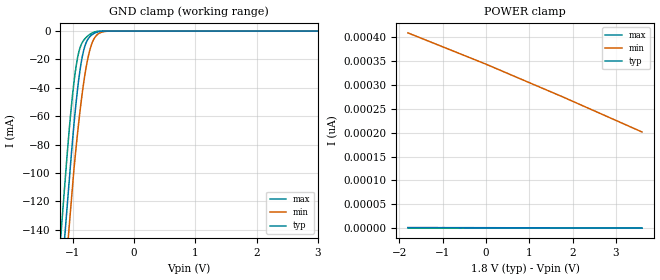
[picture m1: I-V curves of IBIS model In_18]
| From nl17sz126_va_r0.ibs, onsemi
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|//////////////////////////////////////////////////////////////////////////////
|//////////////////////////////////////////////////////////////////////////////
[Model]  In_18
Model_type Input
Vinh =  1.17
Vinl =  0.63
|  variable   typ   min   max
C_comp   2.6pF   2.6pF   2.6pF
|//////////////////////////////////////////////////////////////////////////////
[Temperature Range]   25   125   -55
|//////////////////////////////////////////////////////////////////////////////
[Voltage Range]   1.80V   1.65V   1.95V
|//////////////////////////////////////////////////////////////////////////////
[POWER Clamp Reference] 1.80V   1.65V   1.95V
|//////////////////////////////////////////////////////////////////////////////
[GND Clamp Reference]   0V   0V   0V
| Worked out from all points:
|   GND clamp passes 1 mA (typ) near -0.62 V on its own axis
|//////////////////////////////////////////////////////////////////////////////
[GND Clamp]
|   Voltage   I(typ)   I(min)   I(max)
-2V       -613.5mA   -628.6mA   -592.9mA
-1.22V    -193.3mA   -222.4mA   -158.8mA
-1.18V    -171.8mA   -201.5mA   -136.5mA
-1.12V    -139.5mA   -170.3mA   -103.1mA
-1.06V    -107.1mA   -139mA     -71.09mA
-960mV    -56.79mA   -88.47mA   -29.4mA
-880mV    -27.22mA   -56.09mA   -11.66mA
-800mV    -10.34mA   -30.41mA   -5.326mA
-700mV    -3.054mA   -10.3mA    -1.722mA
-600mV    -709.9uA   -2.508mA   -209.3uA
-420mV    -3.627uA   -71.28uA   -127.6nA
4V        1.285pA    434.4pA    184.2fA
|//////////////////////////////////////////////////////////////////////////////
[POWER Clamp]
|   Voltage   I(typ)   I(min)   I(max)
-1.8V     1.206pA    408.9pA    166.2fA
0V        850.5fA    343.4pA    85.17fA
1.8V      494.8fA    273.7pA    4.109fA
3.6V      139.1fA    201.4pA    -76.95fA
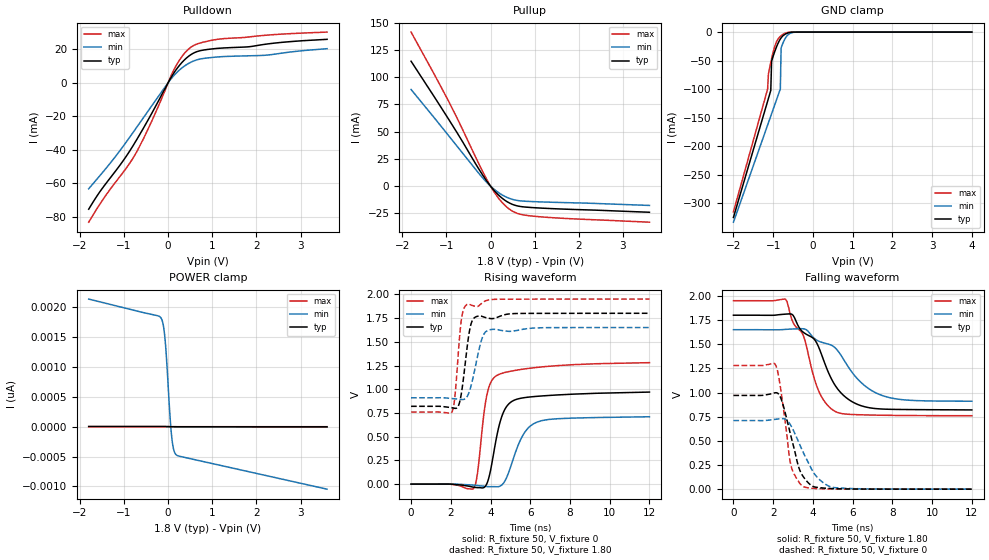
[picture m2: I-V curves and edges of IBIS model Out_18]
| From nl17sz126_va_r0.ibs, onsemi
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|//////////////////////////////////////////////////////////////////////////////
|//////////////////////////////////////////////////////////////////////////////
[Model] Out_18
Model_type 3-state
Polarity Non-Inverting
Enable Active-High
Vmeas = 0.90
Vref = 1.8
Rref = 500
Cref = 50pF
|  variable   typ   min   max
C_comp   3.9pF   3.9pF   3.9pF
|//////////////////////////////////////////////////////////////////////////////
[Temperature Range]   25   125   -55
|//////////////////////////////////////////////////////////////////////////////
[Voltage Range]   1.80V   1.65V   1.95V
|//////////////////////////////////////////////////////////////////////////////
[Pulldown Reference]   0V   0V   0V
|//////////////////////////////////////////////////////////////////////////////
[Pullup Reference]   1.80V   1.65V   1.95V
|//////////////////////////////////////////////////////////////////////////////
[GND Clamp Reference]   0V   0V   0V
|//////////////////////////////////////////////////////////////////////////////
[POWER Clamp Reference] 1.80V   1.65V   1.95V
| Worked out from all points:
|   slope of the pulldown table from 0 to 0.27 V, typ, clamps not added: 25 ohm
|   slope of the pullup table from 0 to 0.27 V, typ, clamps not added: 23.9 ohm
|   GND clamp passes 1 mA (typ) near -0.60 V on its own axis
|   falling waveform, R_fixture 50, V_fixture 1.80: 20-80 % time 1.67ns typ, 1.93ns min, 1.29ns max; typ from 1.8 V to 0.82 V
|   falling waveform, R_fixture 50, V_fixture 0: 20-80 % time 722ps typ, 1.03ns min, 498ps max; typ from 0.97 V to 0 V
|   rising waveform, R_fixture 50, V_fixture 0: 20-80 % time 646ps typ, 855ps min, 499ps max; typ from 0 V to 0.97 V
|   rising waveform, R_fixture 50, V_fixture 1.80: 20-80 % time 356ps typ, 478ps min, 279ps max; typ from 0.82 V to 1.8 V
|//////////////////////////////////////////////////////////////////////////////
[Pulldown]
|   Voltage   I(typ)   I(min)   I(max)
-1.8V     -75.54mA   -63.35mA   -83.29mA
-1.45V    -61.61mA   -52.47mA   -68.7mA
-1.05V    -47.73mA   -39.08mA   -54.57mA
-790mV    -37.4mA    -29.54mA   -44.8mA
-460mV    -22.5mA    -17.14mA   -27.98mA
150mV     6.578mA    4.834mA    8.675mA
330mV     12.56mA    9.171mA    16.24mA
480mV     16.09mA    11.74mA    20.46mA
690mV     18.84mA    13.9mA     23.39mA
1.12V     20.48mA    15.35mA    25.9mA
2.22V     23.01mA    16.41mA    28.34mA
3.6V      25.88mA    20.3mA     30.2mA
|//////////////////////////////////////////////////////////////////////////////
[Pullup]
|   Voltage   I(typ)   I(min)   I(max)
-1.8V     114.6mA    88.69mA    141.4mA
-960mV    62.08mA    46.84mA    78.73mA
-760mV    49.17mA    36.73mA    62.68mA
-280mV    16.69mA    12.48mA    21.77mA
-40mV     2.125mA    1.556mA    2.846mA
160mV     -7.332mA   -5.342mA   -9.914mA
280mV     -11.61mA   -8.452mA   -15.76mA
400mV     -14.86mA   -10.8mA    -20.26mA
520mV     -17.1mA    -12.41mA   -23.45mA
640mV     -18.42mA   -13.34mA   -25.42mA
1V        -19.82mA   -14.25mA   -27.68mA
3.6V      -23.98mA   -17.71mA   -33.08mA
|//////////////////////////////////////////////////////////////////////////////
[GND Clamp]
|   Voltage   I(typ)   I(min)   I(max)
-2V       -324.9mA   -333.3mA   -315mA
-1.14V    -121.2mA   -163mA     -99.88mA
-1.12V    -116.5mA   -159mA     -73.89mA
-1.06V    -102.2mA   -147.2mA   -52.96mA
-1.04V    -51.21mA   -143.2mA   -46.66mA
-960mV    -34.1mA    -127.4mA   -25.27mA
-820mV    -12.17mA   -99.64mA   -7.555mA
-800mV    -10.11mA   -27.8mA    -6.375mA
-700mV    -3.742mA   -11.47mA   -2.068mA
-620mV    -1.325mA   -4.378mA   -418uA
-380mV    -1.233uA   -37.51uA   -18.43nA
4V        323.3fA    -65.59pA   221.9fA
|//////////////////////////////////////////////////////////////////////////////
[POWER Clamp]
|   Voltage   I(typ)   I(min)   I(max)
-1.8V     4.117pA    2.139nA    202.9fA
-240mV    3.159pA    1.86nA     84.37fA
-160mV    3.11pA     1.82nA     78.3fA
-110mV    3.061pA    1.701nA    74.5fA
-70mV     2.893pA    1.462nA    71.46fA
-30mV     2.356pA    1.06nA     68.42fA
40mV      562.2fA    194.7pA    63.1fA
80mV      -372.3fA   -168.2pA   60.06fA
100mV     -714fA     -286.9pA   58.54fA
130mV     -1.056pA   -397.4pA   56.26fA
190mV     -1.301pA   -476.2pA   51.7fA
3.6V      -3.649pA   -1.047nA   -207.4fA
|//////////////////////////////////////////////////////////////////////////////
|//////////////////////////////////////////////////////////////////////////////
[Ramp]
|  variable   typ   min   max
R_load = 50
dV/dt_r   5.820E-01/6.500E-10  4.260E-01/8.500E-10  7.680E-01/5.000E-10
dV/dt_f   5.880E-01/1.725E-09  4.440E-01/1.950E-09  7.140E-01/1.275E-09
|//////////////////////////////////////////////////////////////////////////////
[Falling Waveform]
R_fixture = 50
V_fixture = 1.80
V_fixture_min = 1.65
V_fixture_max = 1.95
C_fixture = 0p
|   time   V(typ)   V(min)   V(max)
0s        1.8V       1.65V      1.95V
2.625ns   1.811V     1.653V     1.965V
3ns       1.8V       1.658V     1.725V
3.525ns   1.622V     1.66V      1.587V
4.275ns   1.477V     1.533V     1.024V
4.65ns    1.274V     1.508V     889.4mV
5.175ns   1.057V     1.451V     799.2mV
6.3ns     873mV      1.129V     770.3mV
7.425ns   829.8mV    973.9mV    765.2mV
12ns      820mV      910mV      760mV
|//////////////////////////////////////////////////////////////////////////////
[Falling Waveform]
R_fixture = 50
V_fixture = 0
C_fixture = 0p
|   time   V(typ)   V(min)   V(max)
0s        970mV      710mV      1.28V
2.1ns     997.4mV    722.4mV    1.293V
2.2ns     995.9mV    725.1mV    1.24V
2.35ns    958.5mV    729.1mV    1.074V
2.9ns     543.5mV    655.6mV    240.6mV
3.25ns    251.5mV    502mV      87.28mV
3.5ns     133.8mV    385.9mV    28.27mV
4.15ns    20mV       138.8mV    6.418mV
4.95ns    6.178mV    21.12mV    1.968mV
12ns      0V         0V         0V
|//////////////////////////////////////////////////////////////////////////////
[Rising Waveform]
R_fixture = 50
V_fixture = 0
C_fixture = 0p
|   time   V(typ)   V(min)   V(max)
0s        0V         0V         0V
3.15ns    -32.59mV   -10.29mV   -44.69mV
3.35ns    -36.72mV   -15.08mV   124.1mV
3.8ns     -1.854mV   -24.88mV   922.8mV
4ns       144.1mV    -26.92mV   1.067V
4.35ns    542.1mV    -27.5mV    1.149V
4.95ns    851.7mV    144.8mV    1.187V
5.6ns     907.9mV    504.2mV    1.21V
6.35ns    925.5mV    654.5mV    1.23V
12ns      970mV      710mV      1.28V
|//////////////////////////////////////////////////////////////////////////////
[Rising Waveform]
R_fixture = 50
V_fixture = 1.80
V_fixture_min = 1.65
V_fixture_max = 1.95
C_fixture = 0p
|   time   V(typ)   V(min)   V(max)
0s        820mV      910mV      760mV
2.05ns    805.2mV    902.1mV    757.7mV
2.2ns     799.3mV    899.2mV    912.4mV
2.525ns   946.3mV    891.9mV    1.723V
2.825ns   1.447V     923.5mV    1.894V
2.975ns   1.651V     1.003V     1.891V
3.125ns   1.739V     1.128V     1.879V
3.55ns    1.769V     1.52V      1.904V
3.9ns     1.748V     1.624V     1.941V
12ns      1.8V       1.65V      1.95V
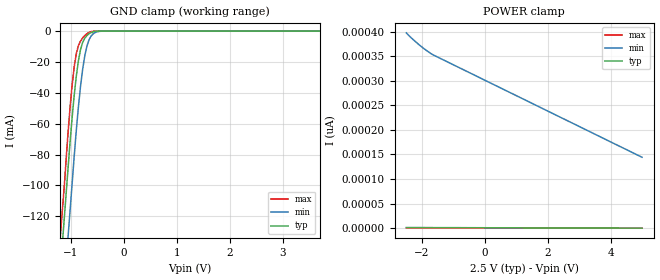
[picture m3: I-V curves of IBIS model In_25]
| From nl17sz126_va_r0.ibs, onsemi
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|//////////////////////////////////////////////////////////////////////////////
|//////////////////////////////////////////////////////////////////////////////
[Model]  In_25
Model_type Input
Vinh =  1.75
Vinl =  0.75
|  variable   typ   min   max
C_comp   2.6pF   2.6pF   2.6pF
|//////////////////////////////////////////////////////////////////////////////
[Temperature Range]   25   125   -55
|//////////////////////////////////////////////////////////////////////////////
[Voltage Range]   2.50V   2.30V   2.70V
|//////////////////////////////////////////////////////////////////////////////
[POWER Clamp Reference] 2.50V   2.30V   2.70V
|//////////////////////////////////////////////////////////////////////////////
[GND Clamp Reference]   0V   0V   0V
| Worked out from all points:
|   GND clamp passes 1 mA (typ) near -0.62 V on its own axis
|//////////////////////////////////////////////////////////////////////////////
[GND Clamp]
|   Voltage   I(typ)   I(min)   I(max)
-2.5V     -743.7mA   -782.7mA   -700.5mA
-1.2V     -154.1mA   -198mA     -132mA
-1.14V    -126.9mA   -171mA     -105.7mA
-1.06V    -90.59mA   -135.1mA   -67.55mA
-1.02V    -72.75mA   -117.1mA   -50.15mA
-940mV    -41.62mA   -81.1mA    -23.13mA
-860mV    -19.12mA   -48.96mA   -9.384mA
-780mV    -7.312mA   -24.68mA   -4.407mA
-660mV    -1.749mA   -5.658mA   -891.3uA
-540mV    -164.5uA   -887.9uA   -27.12uA
-380mV    -648.6nA   -20.78uA   -22.45nA
5V        1.197pA    385.8pA    344.2fA
|//////////////////////////////////////////////////////////////////////////////
[POWER Clamp]
|   Voltage   I(typ)   I(min)   I(max)
-2.5V     1.197pA    397.6pA    354fA
-2.32V    1.167pA    386.1pA    345.1fA
-2.08V    1.126pA    372.6pA    335fA
-1.66V    1.056pA    353.2pA    317.5fA
5V        -63.39fA   144.3pA    39.6fA
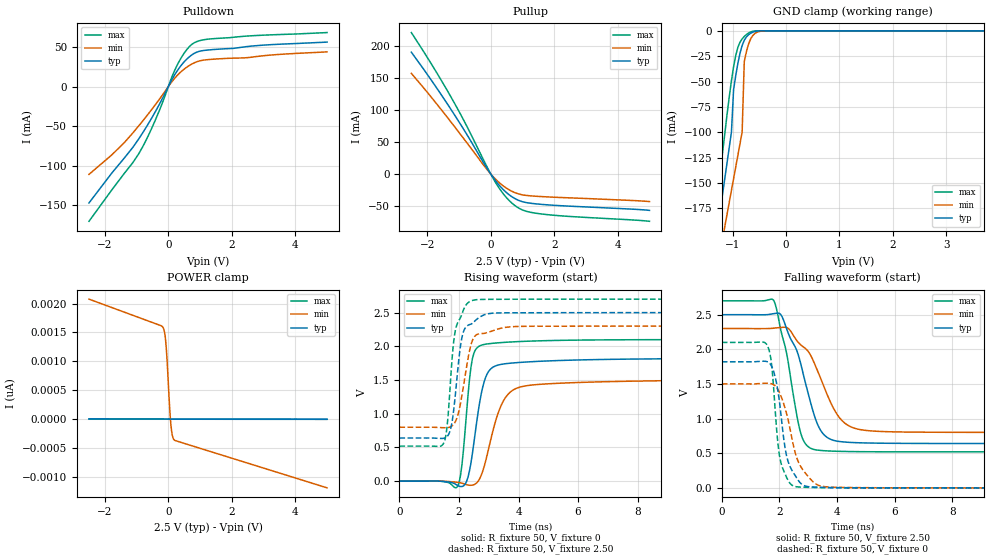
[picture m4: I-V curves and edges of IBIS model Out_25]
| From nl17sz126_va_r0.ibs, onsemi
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|//////////////////////////////////////////////////////////////////////////////
|//////////////////////////////////////////////////////////////////////////////
[Model] Out_25
Model_type 3-state
Polarity Non-Inverting
Enable Active-High
Vmeas = 1.25
Vref = 2.50
Rref = 500
Cref = 50pF
|  variable   typ   min   max
C_comp   3.9pF   3.9pF   3.9pF
|//////////////////////////////////////////////////////////////////////////////
[Temperature Range]   25   125   -55
|//////////////////////////////////////////////////////////////////////////////
[Voltage Range]   2.50V   2.30V   2.70V
|//////////////////////////////////////////////////////////////////////////////
[Pulldown Reference]   0V   0V   0V
|//////////////////////////////////////////////////////////////////////////////
[Pullup Reference]   2.50V   2.30V   2.70V
|//////////////////////////////////////////////////////////////////////////////
[GND Clamp Reference]   0V   0V   0V
|//////////////////////////////////////////////////////////////////////////////
[POWER Clamp Reference] 2.50V   2.30V   2.70V
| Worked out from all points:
|   slope of the pulldown table from 0 to 0.375 V, typ, clamps not added: 14.8 ohm
|   slope of the pullup table from 0 to 0.375 V, typ, clamps not added: 16.1 ohm
|   GND clamp passes 1 mA (typ) near -0.60 V on its own axis
|   falling waveform, R_fixture 50, V_fixture 2.50: 20-80 % time 818ps typ, 1.01ns min, 591ps max; typ from 2.5 V to 0.64 V
|   falling waveform, R_fixture 50, V_fixture 0: 20-80 % time 392ps typ, 593ps min, 270ps max; typ from 1.82 V to 0 V
|   rising waveform, R_fixture 50, V_fixture 0: 20-80 % time 400ps typ, 609ps min, 259ps max; typ from 0 V to 1.82 V
|   rising waveform, R_fixture 50, V_fixture 2.50: 20-80 % time 288ps typ, 364ps min, 262ps max; typ from 0.64 V to 2.5 V
|//////////////////////////////////////////////////////////////////////////////
[Pulldown]
|   Voltage   I(typ)   I(min)   I(max)
-2.5V     -147.3mA   -111.1mA   -170.5mA
-1.78V    -109.4mA   -86.43mA   -130.7mA
-940mV    -66.65mA   -50.08mA   -85.52mA
-680mV    -50.3mA    -37.09mA   -66.13mA
-420mV    -32.52mA   -23.52mA   -43.33mA
100mV     7.86mA     5.548mA    10.91mA
260mV     18.69mA    13.18mA    25.61mA
500mV     31.32mA    22.12mA    42.33mA
740mV     40.06mA    28.47mA    53.33mA
980mV     44.6mA     32.38mA    57.96mA
1.4V      46.76mA    34.56mA    60.51mA
5V        56.22mA    43.84mA    68.29mA
|//////////////////////////////////////////////////////////////////////////////
[Pullup]
|   Voltage   I(typ)   I(min)   I(max)
-2.5V     189.8mA    156.8mA    220.4mA
-1.86V    145.4mA    119mA      170.7mA
-1.18V    95.11mA    76.33mA    113.6mA
-820mV    67.01mA    53.08mA    80.86mA
-160mV    12.36mA    9.64mA     15.35mA
80mV      -5.707mA   -4.391mA   -7.198mA
400mV     -24.55mA   -18.79mA   -31.18mA
740mV     -37.71mA   -28.63mA   -48.39mA
920mV     -41.91mA   -31.63mA   -54.17mA
1.1V      -44.38mA   -33.29mA   -57.82mA
1.64V     -47.54mA   -35.34mA   -62.59mA
5V        -56.71mA   -42.98mA   -73.74mA
|//////////////////////////////////////////////////////////////////////////////
[GND Clamp]
|   Voltage   I(typ)   I(min)   I(max)
-2.5V     -645.5mA   -583mA     -704mA
-1.34V    -217.8mA   -249.4mA   -188.5mA
-1.26V    -188.4mA   -226.4mA   -153mA
-1.14V    -144.1mA   -191.9mA   -99.64mA
-1.02V    -99.88mA   -157.4mA   -49.18mA
-980mV    -58.04mA   -145.9mA   -35.5mA
-900mV    -32.15mA   -122.9mA   -16.32mA
-820mV    -14.52mA   -99.87mA   -7.959mA
-780mV    -9.33mA    -30.27mA   -5.568mA
-660mV    -2.362mA   -7.848mA   -1.103mA
-380mV    -1.024uA   -35.41uA   -22.13nA
5V        654.9fA    128.4pA    408.1fA
|//////////////////////////////////////////////////////////////////////////////
[POWER Clamp]
|   Voltage   I(typ)   I(min)   I(max)
-2.5V     5.002pA    2.077nA    413.6fA
-240mV    2.835pA    1.619nA    351.6fA
-160mV    2.743pA    1.579nA    349.4fA
-100mV    2.583pA    1.432nA    347.8fA
-60mV     2.344pA    1.192nA    346.7fA
-20mV     1.944pA    824.1pA    345.6fA
40mV      1.096pA    206.5pA    343.9fA
80mV      507fA      -96.43pA   342.8fA
100mV     245.1fA    -196.7pA   342.3fA
140mV     -176.6fA   -312.1pA   341.2fA
200mV     -556.4fA   -366pA     339.6fA
5V        -3.252pA   -1.188nA   207.9fA
|//////////////////////////////////////////////////////////////////////////////
|//////////////////////////////////////////////////////////////////////////////
[Ramp]
|  variable   typ   min   max
dV/dt_r   1.092E+00/4.000E-10  9.000E-01/6.500E-10  1.260E+00/2.500E-10
dV/dt_f   1.116E+00/8.000E-10  9.000E-01/1.000E-09  1.308E+00/5.500E-10
R_load = 50
|/////////////////////////////////////////////////////////////////////////////
[Falling Waveform]
R_fixture = 50
V_fixture = 2.50
V_fixture_min = 2.30
V_fixture_max = 2.70
C_fixture = 0p
|   time   V(typ)   V(min)   V(max)
0s        2.5V       2.3V       2.7V
1.8ns     2.515V     2.305V     2.708V
2.1ns     2.466V     2.317V     2.19V
2.25ns    2.298V     2.315V     1.946V
2.7ns     1.857V     2.081V     855.9mV
3.1ns     1.207V     1.902V     568.6mV
3.6ns     747.5mV    1.408V     535.2mV
4.1ns     668.6mV    1.007V     527.1mV
4.65ns    652.6mV    856.1mV    523.1mV
12ns      640mV      800mV      520mV
|//////////////////////////////////////////////////////////////////////////////
[Falling Waveform]
R_fixture = 50
V_fixture = 0
C_fixture = 0p
|   time   V(typ)   V(min)   V(max)
0s        1.82V      1.5V       2.1V
1.6ns     1.818V     1.511V     2.041V
1.75ns    1.738V     1.499V     1.701V
1.9ns     1.514V     1.45V      859mV
2ns       1.252V     1.379V     470.3mV
2.25ns    460.6mV    1.073V     152.1mV
2.5ns     209.9mV    587.5mV    24.99mV
2.85ns    34.04mV    240.4mV    9.136mV
3.5ns     7.132mV    21.13mV    3.033mV
12ns      0V         0V         0V
|//////////////////////////////////////////////////////////////////////////////
[Rising Waveform]
R_fixture = 50
V_fixture = 0
C_fixture = 0p
|   time   V(typ)   V(min)   V(max)
0s        0V         0V         0V
1.95ns    -62.82mV   -17.05mV   -82.46mV
2.1ns     -79.55mV   -29.17mV   244.6mV
2.3ns     54.38mV    -56.86mV   1.257V
2.45ns    406.3mV    -58.64mV   1.815V
2.75ns    1.299V     90.07mV    2.016V
3ns       1.631V     489.5mV    2.039V
3.4ns     1.731V     1.106V     2.055V
4ns       1.76V      1.389V     2.07V
12ns      1.82V      1.5V       2.1V
|//////////////////////////////////////////////////////////////////////////////
[Rising Waveform]
R_fixture = 50
V_fixture = 2.50
V_fixture_min = 2.30
V_fixture_max = 2.70
C_fixture = 0p
|   time   V(typ)   V(min)   V(max)
0s        640mV      800mV      520mV
1.5ns     637.1mV    792.7mV    577.6mV
1.6ns     661.5mV    793.7mV    810.7mV
1.725ns   784.4mV    808.5mV    1.548V
1.875ns   1.269V     879.6mV    2.228V
2.1ns     2.132V     1.273V     2.478V
2.4ns     2.329V     2.017V     2.673V
2.625ns   2.411V     2.179V     2.693V
3.75ns    2.497V     2.29V      2.698V
12ns      2.5V       2.3V       2.7V
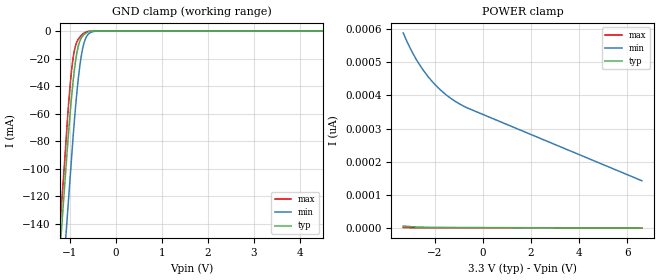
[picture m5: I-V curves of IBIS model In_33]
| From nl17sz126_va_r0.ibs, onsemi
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|//////////////////////////////////////////////////////////////////////////////
|//////////////////////////////////////////////////////////////////////////////
[Model]  In_33
Model_type Input
Vinh = 2.31
Vinl = 0.99
|  variable   typ   min   max
C_comp   2.6pF   2.6pF   2.6pF
|//////////////////////////////////////////////////////////////////////////////
[Temperature Range]   25   125   -55
|//////////////////////////////////////////////////////////////////////////////
[Voltage Range]   3.30V   3.00V   3.60V
|//////////////////////////////////////////////////////////////////////////////
[POWER Clamp Reference] 3.30V   3.00V   3.60V
|//////////////////////////////////////////////////////////////////////////////
[GND Clamp Reference]   0V   0V   0V
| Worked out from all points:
|   GND clamp passes 1 mA (typ) near -0.62 V on its own axis
|//////////////////////////////////////////////////////////////////////////////
[GND Clamp]
|   Voltage   I(typ)   I(min)   I(max)
-3.3V     -1.132A    -1.169A    -1.093A
-1.26V    -182.7mA   -230.6mA   -163.8mA
-1.2V     -154.7mA   -203mA     -136.4mA
-1.16V    -136.1mA   -184.6mA   -118.2mA
-1.08V    -98.92mA   -147.9mA   -79.91mA
-980mV    -55.88mA   -101.9mA   -35.76mA
-900mV    -29mA      -66.13mA   -14.55mA
-840mV    -15.18mA   -43.39mA   -7.657mA
-760mV    -5.795mA   -20.75mA   -3.591mA
-640mV    -1.319mA   -4.39mA    -582.6uA
-380mV    -672.7nA   -22.08uA   -20.84nA
6.6V      1.925pA    451.9pA    564.4fA
|//////////////////////////////////////////////////////////////////////////////
[POWER Clamp]
|   Voltage   I(typ)   I(min)   I(max)
-3.3V     5.92pA     588.6pA    1.449pA
-3.08V    4.52pA     552.8pA    983.7fA
-2.84V    3.331pA    519.2pA    692.2fA
-2.6V     2.547pA    490.3pA    551.6fA
-2.32V    1.984pA    461.7pA    518.1fA
-2.04V    1.641pA    437.4pA    499.1fA
-1.72V    1.527pA    414.4pA    477.3fA
-1.44V    1.457pA    397.3pA    458.3fA
-1.08V    1.366pA    379.4pA    433.8fA
-640mV    1.255pA    362.2pA    403.8fA
6.6V      -569.2fA   142.5pA    -88.72fA
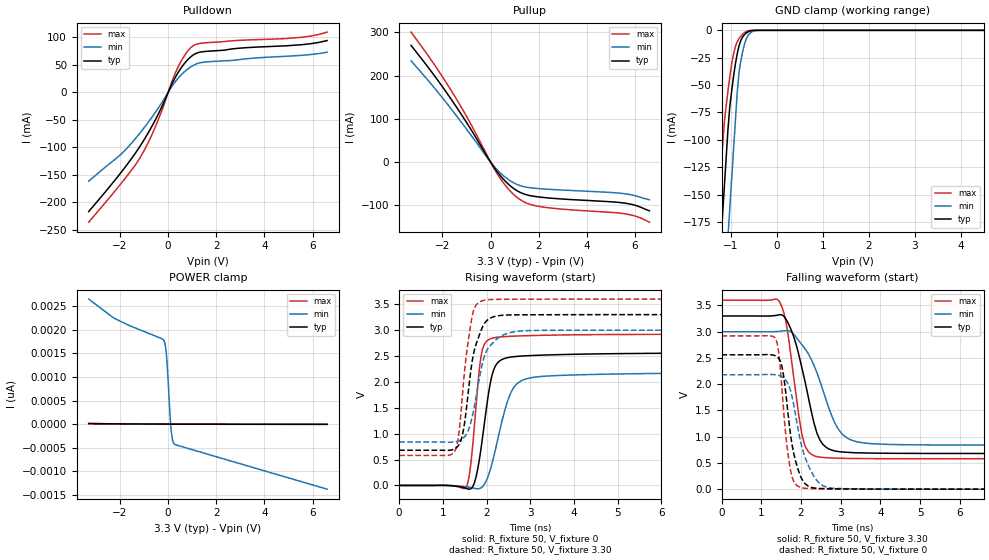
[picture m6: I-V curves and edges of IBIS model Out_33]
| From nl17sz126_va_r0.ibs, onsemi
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|//////////////////////////////////////////////////////////////////////////////
|//////////////////////////////////////////////////////////////////////////////
[Model] Out_33
Model_type 3-state
Polarity Non-Inverting
Enable Active-High
Vmeas = 1.65
Vref = 3.30
Rref = 500
Cref = 50pF
|  variable   typ   min   max
C_comp   3.9pF   3.9pF   3.9pF
|//////////////////////////////////////////////////////////////////////////////
[Temperature Range]   25   125   -55
|//////////////////////////////////////////////////////////////////////////////
[Voltage Range]   3.30V   3.00V   3.60V
|//////////////////////////////////////////////////////////////////////////////
[Pulldown Reference]   0V   0V   0V
|//////////////////////////////////////////////////////////////////////////////
[Pullup Reference]   3.30V   3.00V   3.60V
|//////////////////////////////////////////////////////////////////////////////
[GND Clamp Reference]   0V   0V   0V
|//////////////////////////////////////////////////////////////////////////////
[POWER Clamp Reference] 3.30V   3.00V   3.60V
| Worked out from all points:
|   slope of the pulldown table from 0 to 0.495 V, typ, clamps not added: 11.9 ohm
|   slope of the pullup table from 0 to 0.495 V, typ, clamps not added: 13.2 ohm
|   GND clamp passes 1 mA (typ) near -0.60 V on its own axis
|   falling waveform, R_fixture 50, V_fixture 3.30: 20-80 % time 478ps typ, 654ps min, 326ps max; typ from 3.3 V to 0.68 V
|   falling waveform, R_fixture 50, V_fixture 0: 20-80 % time 290ps typ, 413ps min, 213ps max; typ from 2.56 V to 0 V
|   rising waveform, R_fixture 50, V_fixture 0: 20-80 % time 266ps typ, 404ps min, 187ps max; typ from 0 V to 2.56 V
|   rising waveform, R_fixture 50, V_fixture 3.30: 20-80 % time 284ps typ, 326ps min, 227ps max; typ from 0.68 V to 3.3 V
|//////////////////////////////////////////////////////////////////////////////
[Pulldown]
|   Voltage   I(typ)   I(min)   I(max)
-3.3V     -216.6mA   -161.2mA   -235.8mA
-1.92V    -143.4mA   -110.6mA   -163.5mA
-1.14V    -95.91mA   -72.14mA   -116.5mA
-780mV    -69.82mA   -51.55mA   -86.77mA
-480mV    -45.53mA   -33.06mA   -57.21mA
180mV     17.43mA    12.37mA    22.44mA
360mV     32.21mA    22.86mA    41.17mA
660mV     51.61mA    36.73mA    65.51mA
960mV     65.29mA    46.75mA    82mA
1.5V      74.1mA     54.91mA    89.82mA
5.54V     86.5mA     67.22mA    99.98mA
6.6V      94.1mA     72.95mA    109.5mA
|//////////////////////////////////////////////////////////////////////////////
[Pullup]
|   Voltage   I(typ)   I(min)   I(max)
-3.3V     270.1mA    234.3mA    301mA
-2.24V    193.1mA    165.4mA    217.9mA
-1.48V    132.6mA    111.8mA    151.7mA
-840mV    77.71mA    64.35mA    90mA
120mV     -10.22mA   -8.215mA   -12.28mA
600mV     -43.74mA   -34.78mA   -53.12mA
1.1V      -66.44mA   -51.99mA   -81.92mA
1.48V     -75.71mA   -58.3mA    -94.8mA
1.96V     -80.64mA   -61.39mA   -102.3mA
5.5V      -94.71mA   -72.93mA   -119.3mA
6.1V      -101.9mA   -79.58mA   -126.9mA
6.6V      -113mA     -87.62mA   -139.4mA
|//////////////////////////////////////////////////////////////////////////////
[GND Clamp]
|   Voltage   I(typ)   I(min)   I(max)
-3.3V     -1.579A    -1.655A    -1.498A
-1.34V    -276.5mA   -371.7mA   -210.7mA
-1.26V    -223.4mA   -319.3mA   -158.2mA
-1.2V     -183.5mA   -280mA     -118.8mA
-1.14V    -143.6mA   -240.7mA   -84.42mA
-1.06V    -90.4mA    -188.4mA   -55.21mA
-1.02V    -69.64mA   -162.2mA   -42.32mA
-940mV    -42.55mA   -109.8mA   -21.71mA
-820mV    -14.25mA   -38.47mA   -7.586mA
-660mV    -2.357mA   -7.594mA   -1.043mA
-380mV    -1.049uA   -35.26uA   -19.34nA
6.6V      1.431pA    146.7pA    595.2fA
|//////////////////////////////////////////////////////////////////////////////
[POWER Clamp]
|   Voltage   I(typ)   I(min)   I(max)
-3.3V     16.42pA    2.655nA    1.504pA
-2.26V    6.493pA    2.253nA    523.7fA
-180mV    2.62pA     1.777nA    322.7fA
-120mV    2.382pA    1.674nA    316.9fA
-80mV     2.156pA    1.517nA    313fA
-60mV     2.02pA     1.402nA    311.1fA
-20mV     1.699pA    1.098nA    307.2fA
80mV      715.6fA    178.8pA    297.6fA
120mV     326.5fA    -94.2pA    293.7fA
180mV     -162.4fA   -326pA     287.9fA
260mV     -580.8fA   -421.5pA   280.2fA
6.6V      -4.736pA   -1.379nA   -332.5fA
|//////////////////////////////////////////////////////////////////////////////
|//////////////////////////////////////////////////////////////////////////////
[Ramp]
|  variable   typ   min   max
dV/dt_r   1.536E+00/2.750E-10  1.308E+00/4.000E-10  1.752E+00/1.750E-10
dV/dt_f   1.572E+00/4.750E-10  1.296E+00/6.000E-10  1.812E+00/3.000E-10
R_load = 50
|/////////////////////////////////////////////////////////////////////////////
[Falling Waveform]
R_fixture = 50
V_fixture = 3.30
V_fixture_min = 3.00
V_fixture_max = 3.60
C_fixture = 0p
|   time   V(typ)   V(min)   V(max)
0s        3.3V       3V         3.6V
1.45ns    3.322V     3.007V     3.58V
1.65ns    3.2V       3.022V     3.067V
2.025ns   2.304V     2.749V     1.037V
2.175ns   1.788V     2.593V     723.8mV
2.325ns   1.266V     2.361V     638mV
2.55ns    854.5mV    1.892V     604.1mV
2.925ns   718.4mV    1.161V     590.1mV
3.375ns   694.2mV    909.2mV    584mV
10ns      680mV      840mV      580mV
|//////////////////////////////////////////////////////////////////////////////
[Falling Waveform]
R_fixture = 50
V_fixture = 0
C_fixture = 0p
|   time   V(typ)   V(min)   V(max)
0s        2.56V      2.18V      2.92V
1.35ns    2.544V     2.18V      2.88V
1.425ns   2.506V     2.169V     2.678V
1.525ns   2.32V      2.139V     1.874V
1.625ns   1.781V     2.068V     974.9mV
1.725ns   1.111V     1.905V     409.9mV
2ns       226.9mV    872mV      30.71mV
2.325ns   22.97mV    245.8mV    9.201mV
2.7ns     8.564mV    28.57mV    4.118mV
10ns      0V         0V         0V
|//////////////////////////////////////////////////////////////////////////////
[Rising Waveform]
R_fixture = 50
V_fixture = 0
C_fixture = 0p
|   time   V(typ)   V(min)   V(max)
0s        0V         0V         0V
1.525ns   -54.24mV   -24.79mV   -44.68mV
1.65ns    -57.78mV   -41.96mV   496.3mV
1.75ns    132.4mV    -60.57mV   1.438V
1.875ns   724.6mV    -46.21mV   2.5V
2.1ns     2.036V     346.1mV    2.836V
2.25ns    2.365V     867.6mV    2.863V
2.525ns   2.476V     1.729V     2.88V
2.925ns   2.505V     2.063V     2.892V
10ns      2.56V      2.18V      2.92V
|//////////////////////////////////////////////////////////////////////////////
[Rising Waveform]
R_fixture = 50
V_fixture = 3.30
V_fixture_min = 3.00
V_fixture_max = 3.60
C_fixture = 0p
|   time   V(typ)   V(min)   V(max)
0s        680mV      840mV      580mV
1.275ns   708.4mV    841.9mV    667.6mV
1.35ns    764.6mV    857mV      901.9mV
1.45ns    982.8mV    901.8mV    1.765V
1.65ns    2.28V      1.246V     3.172V
1.75ns    2.7V       1.661V     3.471V
1.9ns     3.047V     2.34V      3.567V
2.225ns   3.272V     2.821V     3.594V
2.775ns   3.296V     2.982V     3.597V
10ns      3.3V       3V         3.6V
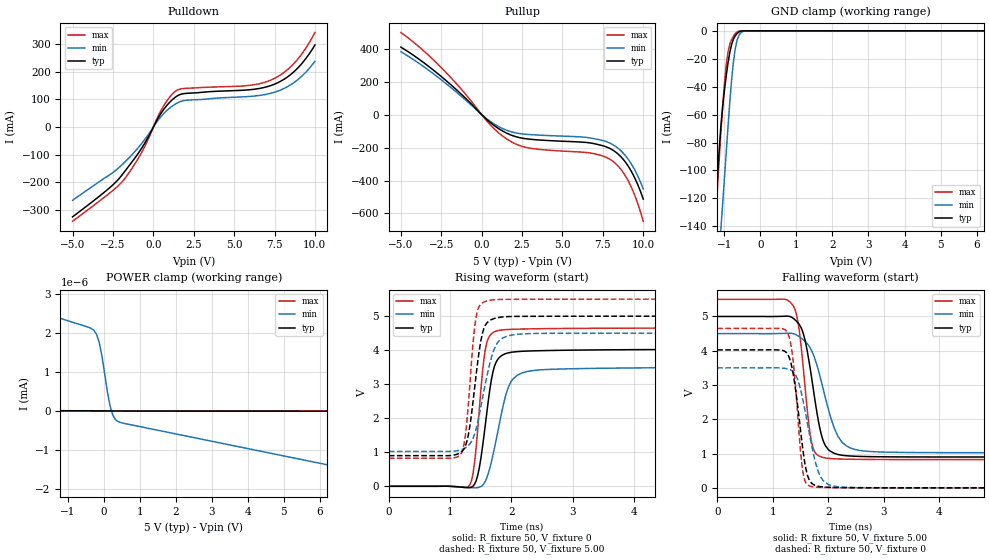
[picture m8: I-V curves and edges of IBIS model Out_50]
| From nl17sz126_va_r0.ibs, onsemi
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|//////////////////////////////////////////////////////////////////////////////
|//////////////////////////////////////////////////////////////////////////////
[Model] Out_50
Model_type 3-state
Polarity Non-Inverting
Enable Active-High
Vmeas = 2.50
Vref = 5.00
Rref = 500
Cref = 50pF
|  variable   typ   min   max
C_comp   3.9pF   3.9pF   3.9pF
|//////////////////////////////////////////////////////////////////////////////
[Temperature Range]   25   125   -55
|//////////////////////////////////////////////////////////////////////////////
[Voltage Range]   5.00V   4.50V   5.50V
|//////////////////////////////////////////////////////////////////////////////
[Pulldown Reference]   0V   0V   0V
|//////////////////////////////////////////////////////////////////////////////
[Pullup Reference]   5.00V   4.50V   5.50V
|//////////////////////////////////////////////////////////////////////////////
[GND Clamp Reference]   0V   0V   0V
|//////////////////////////////////////////////////////////////////////////////
[POWER Clamp Reference] 5.00V   4.50V   5.50V
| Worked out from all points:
|   slope of the pulldown table from 0 to 0.75 V, typ, clamps not added: 10.4 ohm
|   slope of the pullup table from 0 to 0.75 V, typ, clamps not added: 11.6 ohm
|   GND clamp passes 1 mA (typ) near -0.61 V on its own axis
|   falling waveform, R_fixture 50, V_fixture 5.00: 20-80 % time 252ps typ, 365ps min, 179ps max; typ from 5 V to 0.9 V
|   falling waveform, R_fixture 50, V_fixture 0: 20-80 % time 191ps typ, 265ps min, 143ps max; typ from 4.03 V to 0 V
|   rising waveform, R_fixture 50, V_fixture 0: 20-80 % time 182ps typ, 257ps min, 138ps max; typ from 0 V to 4.03 V
|   rising waveform, R_fixture 50, V_fixture 5.00: 20-80 % time 175ps typ, 249ps min, 129ps max; typ from 0.9 V to 5 V
|//////////////////////////////////////////////////////////////////////////////
[Pulldown]
|   Voltage   I(typ)   I(min)   I(max)
-5V       -325.1mA   -265mA     -341.1mA
-2.75V    -222mA     -174.6mA   -241mA
-1.85V    -166.7mA   -131.5mA   -192.7mA
-725mV    -76.48mA   -59.59mA   -91.84mA
550mV     56.45mA    43.11mA    68.35mA
1.375V    108.8mA    83.73mA    130.2mA
1.975V    121.8mA    96.58mA    140.2mA
5.95V     135.2mA    110.9mA    151.1mA
7.3V      151mA      123mA      170.9mA
8.05V     171.8mA    138.8mA    196.2mA
8.8V      205.8mA    165.3mA    236.6mA
10V       297.2mA    238.2mA    342.3mA
|//////////////////////////////////////////////////////////////////////////////
[Pullup]
|   Voltage   I(typ)   I(min)   I(max)
-5V       410.1mA    382.2mA    498.3mA
-2.6V     239.3mA    218.9mA    294.8mA
-1.25V    122.8mA    110.2mA    153.1mA
400mV     -36.89mA   -31.97mA   -47.46mA
1.75V     -121.3mA   -101.8mA   -160.2mA
3.1V      -150.3mA   -121.8mA   -205.3mA
6.875V    -174.6mA   -144.5mA   -235.5mA
8.125V    -216mA     -182.7mA   -283.7mA
8.625V    -256.5mA   -220mA     -333.2mA
9.125V    -321.4mA   -278.8mA   -412.6mA
9.625V    -417.1mA   -365.4mA   -530.2mA
10V       -512.9mA   -451.9mA   -647.5mA
|//////////////////////////////////////////////////////////////////////////////
[GND Clamp]
|   Voltage   I(typ)   I(min)   I(max)
-5V       -1.662A    -1.589A    -1.731A
-1.275V   -138.7mA   -207.9mA   -147.6mA
-1.2V     -108mA     -180mA     -115.8mA
-1.1V     -69.05mA   -143mA     -73.67mA
-1V       -42.76mA   -105.9mA   -38.05mA
-900mV    -23.08mA   -68.81mA   -15.15mA
-800mV    -9.782mA   -35.12mA   -6.329mA
-750mV    -6.039mA   -22.4mA    -3.849mA
-700mV    -3.599mA   -13.02mA   -2.005mA
-600mV    -885.4uA   -3.43mA    -222.4uA
-350mV    -343.1nA   -15.28uA   -7.12nA
10V       3.97pA     826.6pA    1.045pA
|//////////////////////////////////////////////////////////////////////////////
[POWER Clamp]
|   Voltage   I(typ)   I(min)   I(max)
-5V       924.5uA    7.516nA    28.34mA
-4.625V   9.76nA     5.857nA    18.71mA
-4.25V    1.234nA    4.83nA     5.473mA
-3.725V   379pA      3.942nA    20.16nA
-3.65V    323pA      3.848nA    501.1pA
-3.575V   276pA      3.759nA    260.9pA
-3.125V   112.8pA    3.327nA    79.26pA
-275mV    4.716pA    2.077nA    621.3fA
-125mV    3.929pA    1.766nA    606.2fA
175mV     874.2fA    138.5pA    576.2fA
400mV     -364.1fA   -272.5pA   553.6fA
10V       -8.008pA   -2.098nA   -408.7fA
|//////////////////////////////////////////////////////////////////////////////
|//////////////////////////////////////////////////////////////////////////////
[Ramp]
|  variable   typ   min   max
dV/dt_r   2.415E+00/1.750E-10 2.100E+00/2.750E-10   2.790E+00/1.500E-10
dV/dt_f   2.460E+00/2.750E-10 2.085E+00/3.500E-10   2.805E+00/1.750E-10
R_load = 50
|/////////////////////////////////////////////////////////////////////////////
[Falling Waveform]
R_fixture = 50
V_fixture = 5.00
V_fixture_min = 4.50
V_fixture_max = 5.50
C_fixture = 0p
|   time   V(typ)   V(min)   V(max)
0s        5V         4.5V       5.5V
1.2ns     5.006V     4.506V     5.506V
1.375ns   4.94V      4.496V     5.295V
1.475ns   4.771V     4.414V     4.624V
1.575ns   4.354V     4.285V     3.073V
1.7ns     3.216V     4.003V     1.329V
1.9ns     1.417V     2.94V      889.5mV
2.175ns   972.5mV    1.5V       843.8mV
2.55ns    918.4mV    1.095V     831.5mV
10ns      900mV      1.025V     825mV
|//////////////////////////////////////////////////////////////////////////////
[Falling Waveform]
R_fixture = 50
V_fixture = 0
C_fixture = 0p
|   time   V(typ)   V(min)   V(max)
0s        4.025V     3.5V       4.65V
1.25ns    3.939V     3.478V     4.562V
1.325ns   3.663V     3.441V     4.199V
1.375ns   3.263V     3.377V     3.603V
1.5ns     1.69V      2.879V     1.079V
1.55ns    1.029V     2.516V     398.8mV
1.675ns   185.4mV    1.449V     48.93mV
1.875ns   30.38mV    286.7mV    14.25mV
2.175ns   9.908mV    29.9mV     6.14mV
10ns      0V         0V         0V
|//////////////////////////////////////////////////////////////////////////////
[Rising Waveform]
R_fixture = 50
V_fixture = 0
C_fixture = 0p
|   time   V(typ)   V(min)   V(max)
0s        0V         0V         0V
1.325ns   -37.17mV   -38.31mV   51.57mV
1.375ns   5.71mV     -45.04mV   388.3mV
1.45ns    316.5mV    -39.89mV   1.653V
1.575ns   1.808V     150.7mV    4.024V
1.675ns   3.145V     726.6mV    4.482V
1.775ns   3.722V     1.573V     4.573V
2ns       3.939V     3.092V     4.612V
2.325ns   3.978V     3.394V     4.627V
10ns      4.025V     3.5V       4.65V
|//////////////////////////////////////////////////////////////////////////////
[Rising Waveform]
R_fixture = 50
V_fixture = 5.00
V_fixture_min = 4.50
V_fixture_max = 5.50
C_fixture = 0p
|   time   V(typ)   V(min)   V(max)
0s        900mV      1.025V     825mV
1.175ns   996.7mV    1.072V     944.5mV
1.25ns    1.184V     1.131V     1.505V
1.325ns   1.798V     1.251V     3.055V
1.425ns   3.278V     1.687V     4.986V
1.525ns   4.475V     2.552V     5.386V
1.625ns   4.844V     3.434V     5.46V
1.8ns     4.963V     4.276V     5.49V
2.175ns   4.994V     4.477V     5.496V
10ns      5V         4.5V       5.5V
